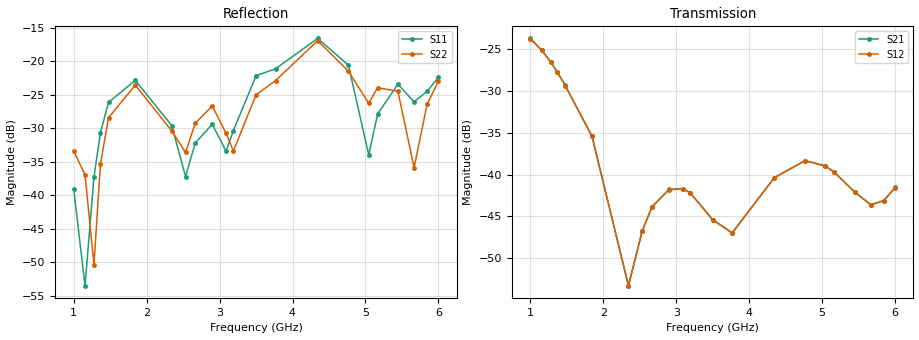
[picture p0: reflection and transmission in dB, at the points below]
!Agilent Technologies,E8364B,MY43040528,A.07.50.67
!Agilent E8364B: A.07.50.67
!Date: Sunday, March 01, 2026 16:19:05
!Correction: S11(Full 2 Port(1,2))
!S21(Full 2 Port(1,2))
!S12(Full 2 Port(1,2))
!S22(Full 2 Port(1,2))
!S2P File: Measurements: S11, S21, S12, S22:
# Hz S  dB  R 50
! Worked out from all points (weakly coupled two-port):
!   451 points, 1 GHz to 6 GHz, reference 50 ohm
!   highest |S21| = -23.71 dB at 1 GHz (marker M1); lowest = -53.3 dB at 2.344 GHz (marker M2)
!   lowest |S11| = -53.5 dB at 1.156 GHz (marker M3), VSWR 1.00, Z = 49.9 + j0.168 ohm
!   |S11| at or under -10 dB: start of sweep to end of sweep
!   |S22| runs from -50.3 to -16.9 dB; largest |S21 - S12| = 0.00028
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1e9  -39.02 33.5  -23.71 152.9  -23.75 153.0  -33.37 0.4
1.155556e9  -53.46 127.7  -25.12 63.9  -25.15 63.9  -36.92 1.3
1.277778e9  -37.29 -163.5  -26.50 -5.6  -26.54 -5.5  -50.32 53.5
1.366667e9  -30.66 -174.4  -27.70 -55.4  -27.73 -55.3  -35.36 109.9
1.477778e9  -26.12 160.8  -29.33 -116.4  -29.36 -116.3  -28.40 83.7
1.844444e9  -22.84 88.2  -35.39 47.5  -35.42 47.5  -23.55 -3.7
2.344444e9  -29.59 26.1  -53.26 -150.2  -53.27 -150.3  -30.38 -79.1
2.533333e9  -37.19 52.7  -46.73 169.2  -46.79 169.2  -33.59 -55.2
2.666667e9  -32.18 82.3  -43.84 104.4  -43.88 104.4  -29.23 -54.6
2.9e9  -29.39 53.7  -41.76 -17.8  -41.80 -17.8  -26.67 -102.3
3.088889e9  -33.41 66.2  -41.67 -118.4  -41.71 -118.3  -30.73 -133.2
3.188889e9  -30.34 89.5  -42.14 -171.1  -42.17 -171.1  -33.38 -118.7
3.5e9  -22.15 56.4  -45.36 37.0  -45.41 37.1  -24.99 -126.6
3.766667e9  -21.12 31.4  -46.94 -66.0  -47.00 -65.9  -22.88 -155.3
4.344444e9  -16.58 -40.1  -40.34 22.4  -40.38 22.4  -16.92 110.5
4.766667e9  -20.59 -109.4  -38.31 146.4  -38.34 146.4  -21.48 35.3
5.044444e9  -33.95 -94.6  -38.94 -17.1  -38.98 -17.0  -26.25 42.1
5.166667e9  -27.85 -54.3  -39.69 -90.8  -39.73 -90.7  -23.94 37.3
5.444444e9  -23.41 -90.3  -42.03 93.2  -42.08 93.3  -24.47 -17.3
5.666667e9  -26.04 -96.4  -43.59 -63.2  -43.62 -63.2  -35.85 -7.1
5.844444e9  -24.48 -85.0  -43.09 167.3  -43.12 167.3  -26.44 25.4
6e9  -22.41 -91.0  -41.53 59.7  -41.57 59.7  -22.94 -1.1
